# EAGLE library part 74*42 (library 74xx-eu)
4-line to 10-line DECODER (1-of-10)

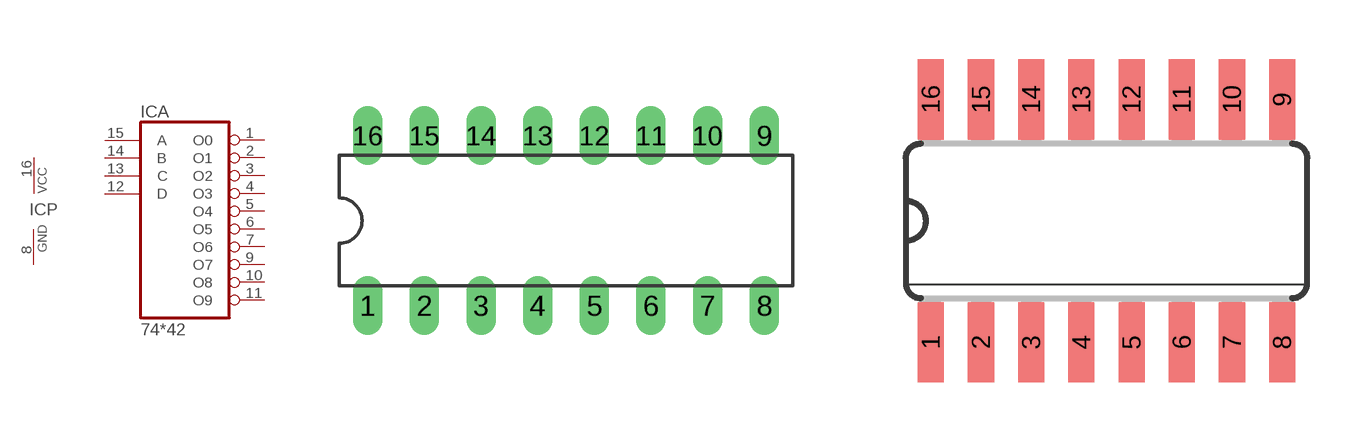
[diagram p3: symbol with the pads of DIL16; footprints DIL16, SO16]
Designator prefix IC; gates A=7442 P=PWRN

## 74AC42N, 74ACT42N, 74HC42N, 74HCT42N, 74LS42N  [DIL16]
1  A:O0  out
2  A:O1  out
3  A:O2  out
4  A:O3  out
5  A:O4  out
6  A:O5  out
7  A:O6  out
8  P:GND  pwr
9  A:O7  out
10  A:O8  out
11  A:O9  out
12  A:D  in
13  A:C  in
14  A:B  in
15  A:A  in
16  P:VCC  pwr

## 74AC42D, 74ACT42D, 74HC42D, 74HCT42D, 74LS42D  [SO16]
Pads as for DIL16

## 74AC42FK, 74ACT42FK, 74HC42FK, 74HCT42FK, 74LS42FK  [LCC20]
2  A:O0  out
3  A:O1  out
4  A:O2  out
5  A:O3  out
7  A:O4  out
8  A:O5  out
9  A:O6  out
10  P:GND  pwr
12  A:O7  out
13  A:O8  out
14  A:O9  out
15  A:D  in
17  A:C  in
18  A:B  in
19  A:A  in
20  P:VCC  pwr

## Footprint DIL16 (pad centres in mm)
Dual In Line Package
drill 0.813 long: 1 -8.89,-3.81; 2 -6.35,-3.81; 3 -3.81,-3.81; 4 -1.27,-3.81; 5 1.27,-3.81; 6 3.81,-3.81; 7 6.35,-3.81; 8 8.89,-3.81; 9 8.89,3.81; 10 6.35,3.81; 11 3.81,3.81; 12 1.27,3.81; 13 -1.27,3.81; 14 -3.81,3.81; 15 -6.35,3.81; 16 -8.89,3.81

## Footprint SO16 (pad centres in mm)
Small Outline package 150 mil
smd 0.66 x 2.032: 1 -4.445,-3.073; 2 -3.175,-3.073; 3 -1.905,-3.073; 4 -0.635,-3.073; 5 0.635,-3.073; 6 1.905,-3.073; 7 3.175,-3.073; 8 4.445,-3.073; 9 4.445,3.073; 10 3.175,3.073; 11 1.905,3.073; 12 0.635,3.073; 13 -0.635,3.073; 14 -1.905,3.073; 15 -3.175,3.073; 16 -4.445,3.073

## Footprint LCC20 (pad centres in mm)
Leadless Chip Carrier Ceramic Package
smd 0.8 x 3.4: 1 0,3.8
smd 0.8 x 2: 2 -1.27,4.5; 3 -2.54,4.5; 9 -2.54,-4.5; 10 -1.27,-4.5; 11 0,-4.5; 12 1.27,-4.5; 13 2.54,-4.5; 19 2.54,4.5; 20 1.27,4.5
smd 2 x 0.8: 4 -4.5,2.54; 5 -4.5,1.27; 6 -4.5,0; 7 -4.5,-1.27; 8 -4.5,-2.54; 14 4.5,-2.54; 15 4.5,-1.27; 16 4.5,0; 17 4.5,1.27; 18 4.5,2.54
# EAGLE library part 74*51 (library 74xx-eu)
AND-OR-INVERT gates/for S-type see 74S51

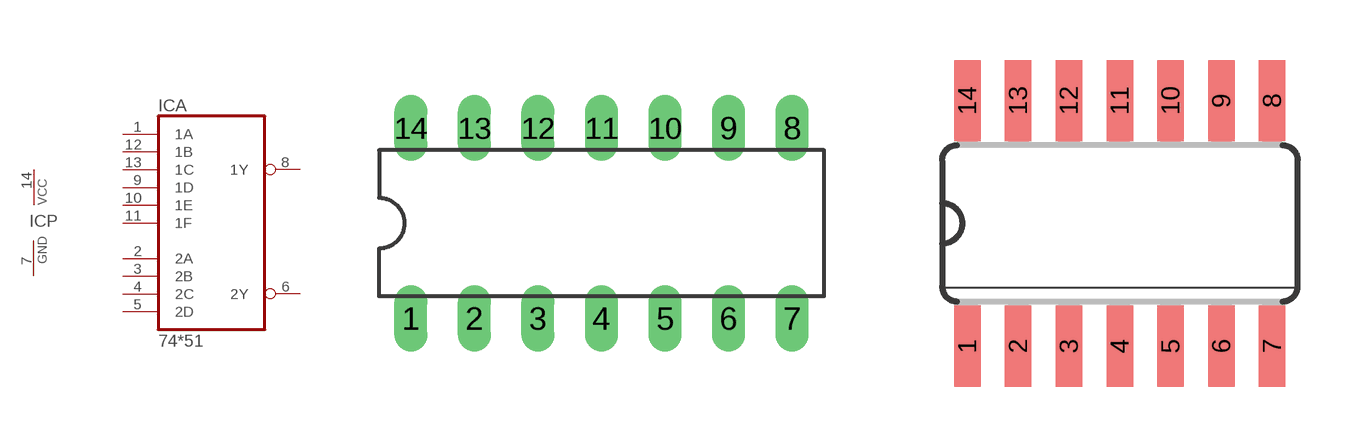
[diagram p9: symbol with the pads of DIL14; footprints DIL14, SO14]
Designator prefix IC; gates A=74LS51 P=PWRN

## 74HC51N, 74LS51N  [DIL14]
1  A:1A  in
2  A:2A  in
3  A:2B  in
4  A:2C  in
5  A:2D  in
6  A:2Y  out
7  P:GND  pwr
8  A:1Y  out
9  A:1D  in
10  A:1E  in
11  A:1F  in
12  A:1B  in
13  A:1C  in
14  P:VCC  pwr

## 74HC51D, 74LS51D  [SO14]
Pads as for DIL14

## 74HC51FK, 74LS51FK  [PLCC20]
2  A:1A  in
3  A:2A  in
4  A:2B  in
6  A:2C  in
8  A:2D  in
9  A:2Y  out
10  P:GND  pwr
12  A:1Y  out
13  A:1D  in
14  A:1E  in
16  A:1F  in
18  A:1B  in
19  A:1C  in
20  P:VCC  pwr

## Footprint DIL14 (pad centres in mm)
Dual In Line Package
drill 0.813 long: 1 -7.62,-3.81; 2 -5.08,-3.81; 3 -2.54,-3.81; 4 0,-3.81; 5 2.54,-3.81; 6 5.08,-3.81; 7 7.62,-3.81; 8 7.62,3.81; 9 5.08,3.81; 10 2.54,3.81; 11 0,3.81; 12 -2.54,3.81; 13 -5.08,3.81; 14 -7.62,3.81

## Footprint SO14 (pad centres in mm)
Small Outline package 150 mil
smd 0.66 x 2.032: 1 -3.81,-3.073; 2 -2.54,-3.073; 3 -1.27,-3.073; 4 0,-3.073; 5 1.27,-3.073; 6 2.54,-3.073; 7 3.81,-3.073; 8 3.81,3.073; 9 2.54,3.073; 10 1.27,3.073; 11 0,3.073; 12 -1.27,3.073; 13 -2.54,3.073; 14 -3.81,3.073

## Footprint PLCC20 (pad centres in mm)
Plastic Leaded Chip Carrier IPC standard
smd 0.6 x 2.2: 1 0,4.3; 2 -1.27,4.3; 3 -2.54,4.3; 9 -2.54,-4.3; 10 -1.27,-4.3; 11 0,-4.3; 12 1.27,-4.3; 13 2.54,-4.3; 19 2.54,4.3; 20 1.27,4.3
smd 2.2 x 0.6: 4 -4.3,2.54; 5 -4.3,1.27; 6 -4.3,0; 7 -4.3,-1.27; 8 -4.3,-2.54; 14 4.3,-2.54; 15 4.3,-1.27; 16 4.3,0; 17 4.3,1.27; 18 4.3,2.54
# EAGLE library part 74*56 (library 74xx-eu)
FREQUENCY DIVIDER

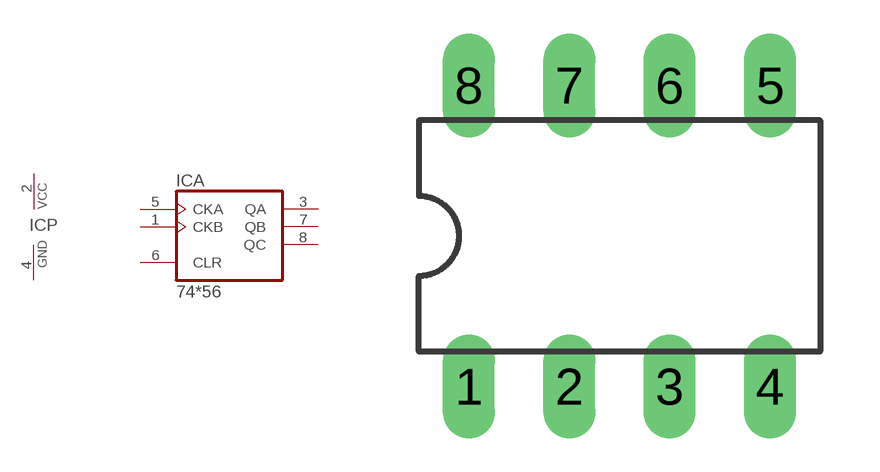
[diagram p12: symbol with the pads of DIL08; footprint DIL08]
Designator prefix IC; gates A=7456 P=PWRN

## 74LS56N  [DIL08]
1  A:CKB  in
2  P:VCC  pwr
3  A:QA  out
4  P:GND  pwr
5  A:CKA  in
6  A:CLR  in
7  A:QB  out
8  A:QC  out

## Footprint DIL08 (pad centres in mm)
Dual In Line Package
drill 0.813 long: 1 -3.81,-3.81; 2 -1.27,-3.81; 3 1.27,-3.81; 4 3.81,-3.81; 5 3.81,3.81; 6 1.27,3.81; 7 -1.27,3.81; 8 -3.81,3.81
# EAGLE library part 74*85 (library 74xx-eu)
4-bit magnitude COMPARATOR

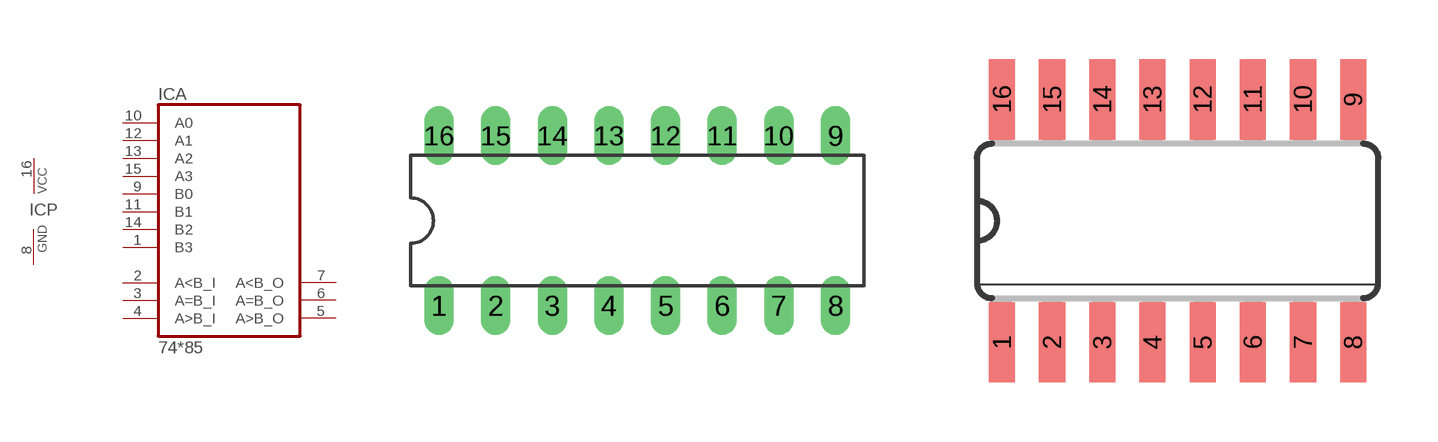
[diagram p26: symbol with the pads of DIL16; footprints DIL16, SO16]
Designator prefix IC; gates A=7485 P=PWRN

## 7485N, 74HC85N, 74HCT85N, 74LS85N, 74S85N  [DIL16]
1  A:B3  in
2  A:A<B_I  in
3  A:A=B_I  in
4  A:A>B_I  in
5  A:A>B_O  out
6  A:A=B_O  out
7  A:A<B_O  out
8  P:GND  pwr
9  A:B0  in
10  A:A0  in
11  A:B1  in
12  A:A1  in
13  A:A2  in
14  A:B2  in
15  A:A3  in
16  P:VCC  pwr

## 74HC85D, 74HCT85D, 74LS85D, 74S85D  [SO16]
Pads as for DIL16

## 74HC85FK, 74HCT85FK, 74LS85FK, 74S85FK  [LCC20]
2  A:B3  in
3  A:A<B_I  in
4  A:A=B_I  in
5  A:A>B_I  in
7  A:A>B_O  out
8  A:A=B_O  out
9  A:A<B_O  out
10  P:GND  pwr
12  A:B0  in
13  A:A0  in
14  A:B1  in
15  A:A1  in
17  A:A2  in
18  A:B2  in
19  A:A3  in
20  P:VCC  pwr

## Footprint DIL16 (pad centres in mm)
Dual In Line Package
drill 0.813 long: 1 -8.89,-3.81; 2 -6.35,-3.81; 3 -3.81,-3.81; 4 -1.27,-3.81; 5 1.27,-3.81; 6 3.81,-3.81; 7 6.35,-3.81; 8 8.89,-3.81; 9 8.89,3.81; 10 6.35,3.81; 11 3.81,3.81; 12 1.27,3.81; 13 -1.27,3.81; 14 -3.81,3.81; 15 -6.35,3.81; 16 -8.89,3.81

## Footprint SO16 (pad centres in mm)
Small Outline package 150 mil
smd 0.66 x 2.032: 1 -4.445,-3.073; 2 -3.175,-3.073; 3 -1.905,-3.073; 4 -0.635,-3.073; 5 0.635,-3.073; 6 1.905,-3.073; 7 3.175,-3.073; 8 4.445,-3.073; 9 4.445,3.073; 10 3.175,3.073; 11 1.905,3.073; 12 0.635,3.073; 13 -0.635,3.073; 14 -1.905,3.073; 15 -3.175,3.073; 16 -4.445,3.073

## Footprint LCC20 (pad centres in mm)
Leadless Chip Carrier Ceramic Package
smd 0.8 x 3.4: 1 0,3.8
smd 0.8 x 2: 2 -1.27,4.5; 3 -2.54,4.5; 9 -2.54,-4.5; 10 -1.27,-4.5; 11 0,-4.5; 12 1.27,-4.5; 13 2.54,-4.5; 19 2.54,4.5; 20 1.27,4.5
smd 2 x 0.8: 4 -4.5,2.54; 5 -4.5,1.27; 6 -4.5,0; 7 -4.5,-1.27; 8 -4.5,-2.54; 14 4.5,-2.54; 15 4.5,-1.27; 16 4.5,0; 17 4.5,1.27; 18 4.5,2.54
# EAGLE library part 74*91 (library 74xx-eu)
8-bit SHIFT REGISTER

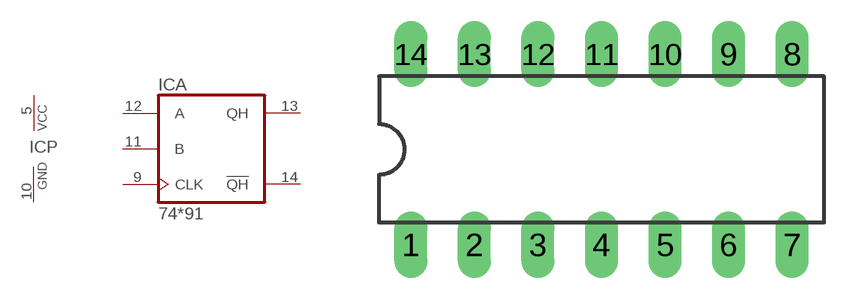
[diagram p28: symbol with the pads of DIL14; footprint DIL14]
Designator prefix IC; gates A=7491 P=PWRN

## 74LS91N  [DIL14]
5  P:VCC  pwr
9  A:CLK  in
10  P:GND  pwr
11  A:B  in
12  A:A  in
13  A:QH  out
14  A:!QH  out

## Footprint DIL14 (pad centres in mm)
Dual In Line Package
drill 0.813 long: 1 -7.62,-3.81; 2 -5.08,-3.81; 3 -2.54,-3.81; 4 0,-3.81; 5 2.54,-3.81; 6 5.08,-3.81; 7 7.62,-3.81; 8 7.62,3.81; 9 5.08,3.81; 10 2.54,3.81; 11 0,3.81; 12 -2.54,3.81; 13 -5.08,3.81; 14 -7.62,3.81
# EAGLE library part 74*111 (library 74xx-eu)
Dual J-K master slave FLIP FLOP, data lockout

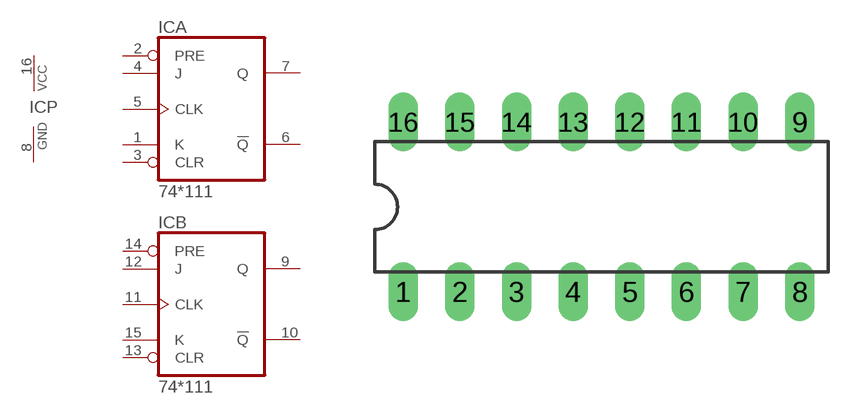
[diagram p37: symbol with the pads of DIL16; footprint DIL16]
Designator prefix IC; gates A=74111 B=74111 P=PWRN

## 74111N  [DIL16]
1  A:K  in
2  A:PRE  in
3  A:CLR  in
4  A:J  in
5  A:CLK  in
6  A:!Q  out
7  A:Q  out
8  P:GND  pwr
9  B:Q  out
10  B:!Q  out
11  B:CLK  in
12  B:J  in
13  B:CLR  in
14  B:PRE  in
15  B:K  in
16  P:VCC  pwr

## Footprint DIL16 (pad centres in mm)
Dual In Line Package
drill 0.813 long: 1 -8.89,-3.81; 2 -6.35,-3.81; 3 -3.81,-3.81; 4 -1.27,-3.81; 5 1.27,-3.81; 6 3.81,-3.81; 7 6.35,-3.81; 8 8.89,-3.81; 9 8.89,3.81; 10 6.35,3.81; 11 3.81,3.81; 12 1.27,3.81; 13 -1.27,3.81; 14 -3.81,3.81; 15 -6.35,3.81; 16 -8.89,3.81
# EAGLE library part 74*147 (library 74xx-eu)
10-line to 4-line and 8-line to 3-line PRIORITY DECODER

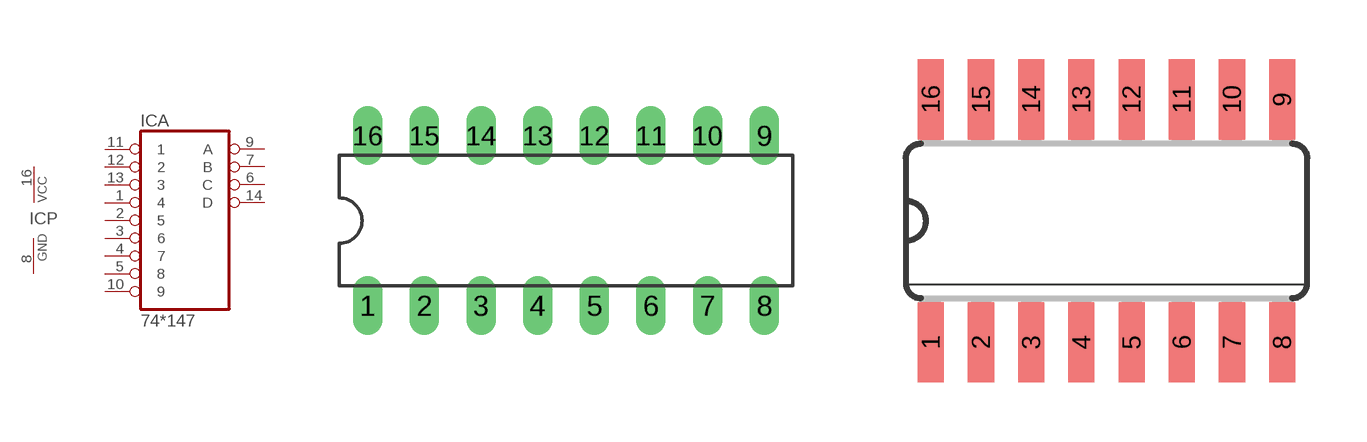
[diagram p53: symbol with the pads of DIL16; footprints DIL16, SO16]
Designator prefix IC; gates A=74147 P=PWRN

## 74147N, 74HC147N, 74HCT147N  [DIL16]
1  A:4  in
2  A:5  in
3  A:6  in
4  A:7  in
5  A:8  in
6  A:C  out
7  A:B  out
8  P:GND  pwr
9  A:A  out
10  A:9  in
11  A:1  in
12  A:2  in
13  A:3  in
14  A:D  out
16  P:VCC  pwr

## 74HC147D, 74HCT147D  [SO16]
Pads as for DIL16

## Footprint DIL16 (pad centres in mm)
Dual In Line Package
drill 0.813 long: 1 -8.89,-3.81; 2 -6.35,-3.81; 3 -3.81,-3.81; 4 -1.27,-3.81; 5 1.27,-3.81; 6 3.81,-3.81; 7 6.35,-3.81; 8 8.89,-3.81; 9 8.89,3.81; 10 6.35,3.81; 11 3.81,3.81; 12 1.27,3.81; 13 -1.27,3.81; 14 -3.81,3.81; 15 -6.35,3.81; 16 -8.89,3.81

## Footprint SO16 (pad centres in mm)
Small Outline package 150 mil
smd 0.66 x 2.032: 1 -4.445,-3.073; 2 -3.175,-3.073; 3 -1.905,-3.073; 4 -0.635,-3.073; 5 0.635,-3.073; 6 1.905,-3.073; 7 3.175,-3.073; 8 4.445,-3.073; 9 4.445,3.073; 10 3.175,3.073; 11 1.905,3.073; 12 0.635,3.073; 13 -0.635,3.073; 14 -1.905,3.073; 15 -3.175,3.073; 16 -4.445,3.073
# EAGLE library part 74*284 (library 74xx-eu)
4 by 4 parallel BINARY MULTIPLIER

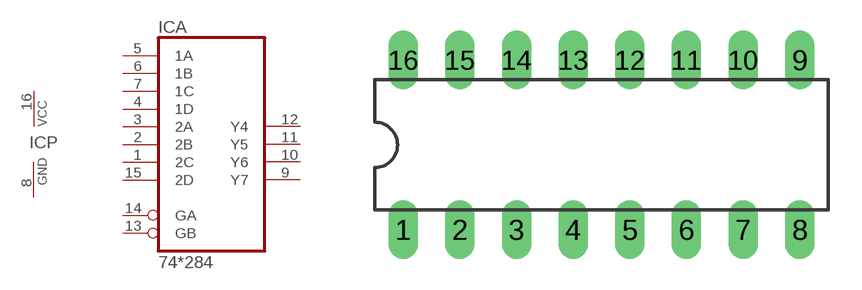
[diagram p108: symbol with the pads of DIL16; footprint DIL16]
Designator prefix IC; gates A=74284 P=PWRN

## 74284N  [DIL16]
1  A:2C  in
2  A:2B  in
3  A:2A  in
4  A:1D  in
5  A:1A  in
6  A:1B  in
7  A:1C  in
8  P:GND  pwr
9  A:Y7  oc
10  A:Y6  oc
11  A:Y5  oc
12  A:Y4  oc
13  A:GB  in
14  A:GA  in
15  A:2D  in
16  P:VCC  pwr

## Footprint DIL16 (pad centres in mm)
Dual In Line Package
drill 0.813 long: 1 -8.89,-3.81; 2 -6.35,-3.81; 3 -3.81,-3.81; 4 -1.27,-3.81; 5 1.27,-3.81; 6 3.81,-3.81; 7 6.35,-3.81; 8 8.89,-3.81; 9 8.89,3.81; 10 6.35,3.81; 11 3.81,3.81; 12 1.27,3.81; 13 -1.27,3.81; 14 -3.81,3.81; 15 -6.35,3.81; 16 -8.89,3.81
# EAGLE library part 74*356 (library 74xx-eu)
8-to 1 line data SELECTOR/MULTIPLEXER/REGISTER, 3-state

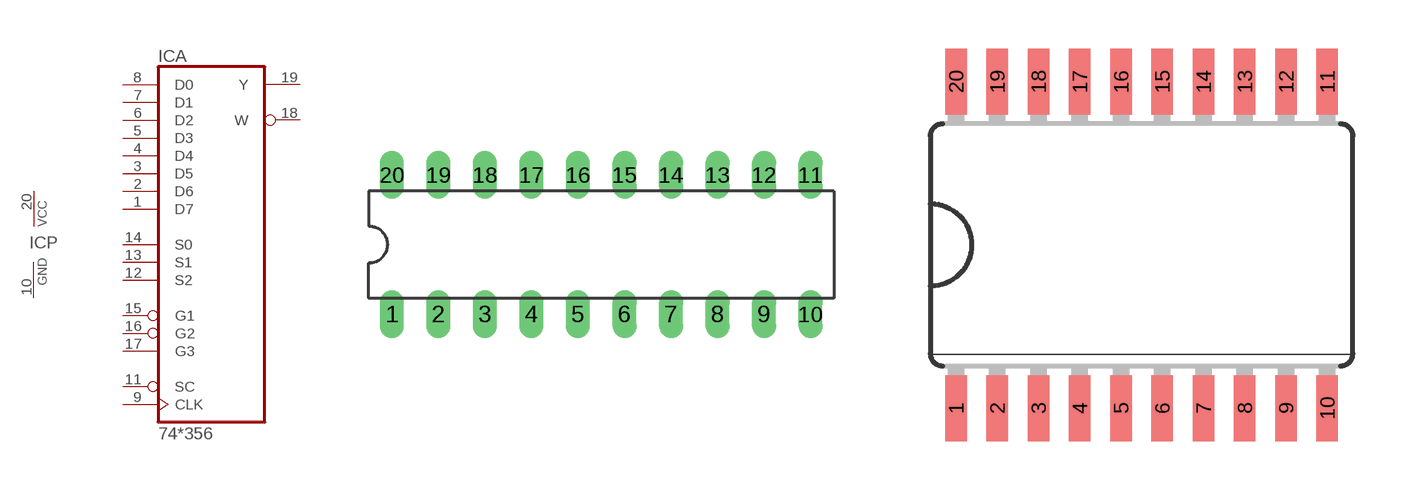
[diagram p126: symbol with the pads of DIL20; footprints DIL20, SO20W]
Designator prefix IC; gates A=74356 P=PWRN

## 74HC356N, 74HCT356N  [DIL20]
1  A:D7  in
2  A:D6  in
3  A:D5  in
4  A:D4  in
5  A:D3  in
6  A:D2  in
7  A:D1  in
8  A:D0  in
9  A:CLK  in
10  P:GND  pwr
11  A:SC  in
12  A:S2  in
13  A:S1  in
14  A:S0  in
15  A:G1  in
16  A:G2  in
17  A:G3  in
18  A:W  hiz
19  A:Y  out
20  P:VCC  pwr

## 74HC356D, 74HCT356D  [SO20W]
Pads as for DIL20

## Footprint DIL20 (pad centres in mm)
Dual In Line Package
drill 0.813 long: 1 -11.43,-3.81; 2 -8.89,-3.81; 3 -6.35,-3.81; 4 -3.81,-3.81; 5 -1.27,-3.81; 6 1.27,-3.81; 7 3.81,-3.81; 8 6.35,-3.81; 9 8.89,-3.81; 10 11.43,-3.81; 11 11.43,3.81; 12 8.89,3.81; 13 6.35,3.81; 14 3.81,3.81; 15 1.27,3.81; 16 -1.27,3.81; 17 -3.81,3.81; 18 -6.35,3.81; 19 -8.89,3.81; 20 -11.43,3.81

## Footprint SO20W (pad centres in mm)
Wide Small Outline package 300 mil
smd 0.66 x 2.032: 1 -5.715,-5.029; 2 -4.445,-5.029; 3 -3.175,-5.029; 4 -1.905,-5.029; 5 -0.635,-5.029; 6 0.635,-5.029; 7 1.905,-5.029; 8 3.175,-5.029; 9 4.445,-5.029; 10 5.715,-5.029; 11 5.715,5.029; 12 4.445,5.029; 13 3.175,5.029; 14 1.905,5.029; 15 0.635,5.029; 16 -0.635,5.029; 17 -1.905,5.029; 18 -3.175,5.029; 19 -4.445,5.029; 20 -5.715,5.029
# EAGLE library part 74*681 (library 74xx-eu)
4-bit parallel binary ACCUMULATOR

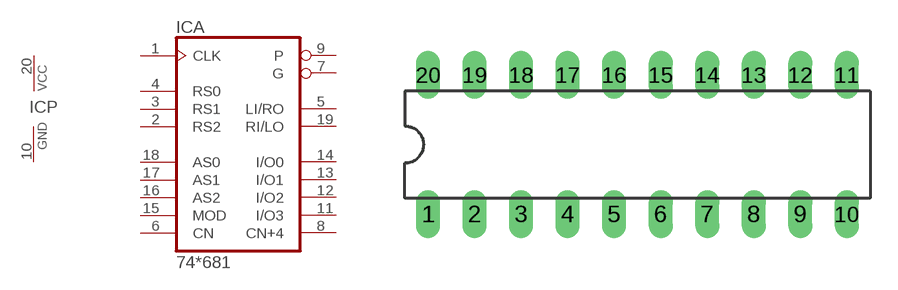
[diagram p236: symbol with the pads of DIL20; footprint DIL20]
Designator prefix IC; gates A=74681 P=PWRN

## 74681N  [DIL20]
1  A:CLK  in
2  A:RS2  in
3  A:RS1  in
4  A:RS0  in
5  A:LI/RO
6  A:CN  in
7  A:G  out
8  A:CN+4  out
9  A:P  out
10  P:GND  pwr
11  A:I/O3
12  A:I/O2
13  A:I/O1
14  A:I/O0
15  A:MOD  in
16  A:AS2  in
17  A:AS1  in
18  A:AS0  in
19  A:RI/LO
20  P:VCC  pwr

## Footprint DIL20 (pad centres in mm)
Dual In Line Package
drill 0.813 long: 1 -11.43,-3.81; 2 -8.89,-3.81; 3 -6.35,-3.81; 4 -3.81,-3.81; 5 -1.27,-3.81; 6 1.27,-3.81; 7 3.81,-3.81; 8 6.35,-3.81; 9 8.89,-3.81; 10 11.43,-3.81; 11 11.43,3.81; 12 8.89,3.81; 13 6.35,3.81; 14 3.81,3.81; 15 1.27,3.81; 16 -1.27,3.81; 17 -3.81,3.81; 18 -6.35,3.81; 19 -8.89,3.81; 20 -11.43,3.81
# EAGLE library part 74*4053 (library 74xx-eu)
Triple 2-channel analog multiplexer/demultiplexer Philips Semiconductor

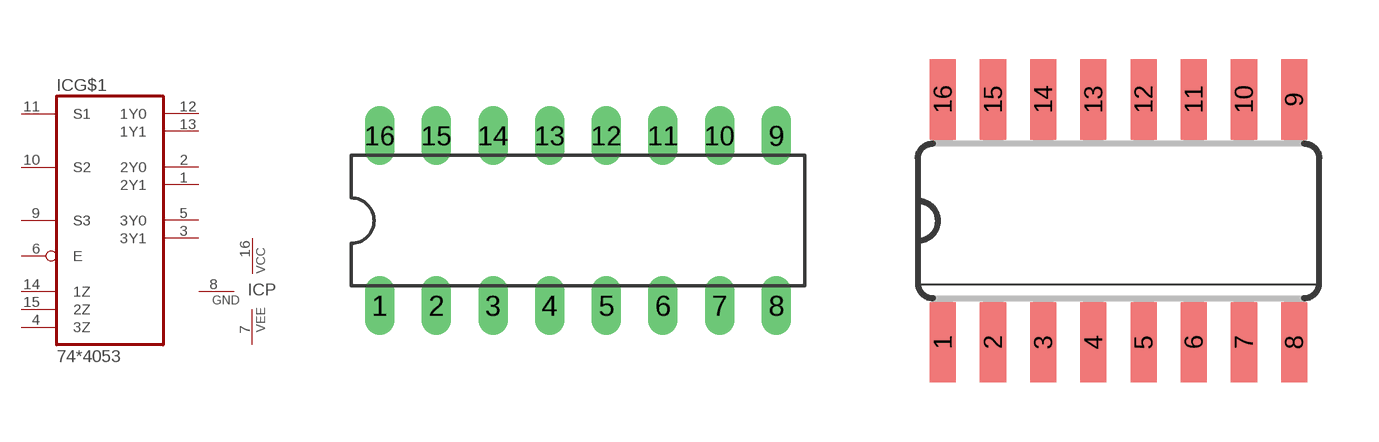
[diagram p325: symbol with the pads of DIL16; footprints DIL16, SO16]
Designator prefix IC; gates G$1=744053 P=PWRVCCGNDVEE

## 74HC4053P, 74HCT4053P  [DIL16]
1  G$1:2Y1
2  G$1:2Y0
3  G$1:3Y1
4  G$1:3Z  in
5  G$1:3Y0
6  G$1:E  in
7  P:VEE  pwr
8  P:GND  pwr
9  G$1:S3
10  G$1:S2
11  G$1:S1
12  G$1:1Y0
13  G$1:1Y1
14  G$1:1Z  in
15  G$1:2Z  in
16  P:VCC  pwr

## 744053D  [SO16]
Pads as for DIL16

## Footprint DIL16 (pad centres in mm)
Dual In Line Package
drill 0.813 long: 1 -8.89,-3.81; 2 -6.35,-3.81; 3 -3.81,-3.81; 4 -1.27,-3.81; 5 1.27,-3.81; 6 3.81,-3.81; 7 6.35,-3.81; 8 8.89,-3.81; 9 8.89,3.81; 10 6.35,3.81; 11 3.81,3.81; 12 1.27,3.81; 13 -1.27,3.81; 14 -3.81,3.81; 15 -6.35,3.81; 16 -8.89,3.81

## Footprint SO16 (pad centres in mm)
Small Outline package 150 mil
smd 0.66 x 2.032: 1 -4.445,-3.073; 2 -3.175,-3.073; 3 -1.905,-3.073; 4 -0.635,-3.073; 5 0.635,-3.073; 6 1.905,-3.073; 7 3.175,-3.073; 8 4.445,-3.073; 9 4.445,3.073; 10 3.175,3.073; 11 1.905,3.073; 12 0.635,3.073; 13 -0.635,3.073; 14 -1.905,3.073; 15 -3.175,3.073; 16 -4.445,3.073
